VERSION 5.8 ;
BUSBITCHARS "[]" ;
DIVIDERCHAR "/" ;
UNITS
    DATABASE MICRONS 1000 ;
END UNITS

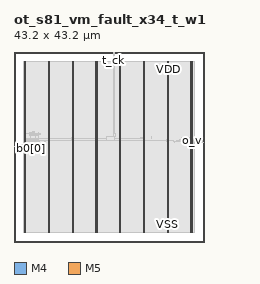
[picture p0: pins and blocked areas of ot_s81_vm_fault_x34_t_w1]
MACRO ot_s81_vm_fault_x34_t_w1
  FOREIGN ot_s81_vm_fault_x34_t_w1 0 0 ;
  CLASS BLOCK ;
  SIZE 43.2 BY 43.2 ;
  PIN b0[0]
    DIRECTION INPUT ;
    USE SIGNAL ;
    PORT
      LAYER M4 ;
        RECT  0 21.36 0.084 21.384 ;
    END
  END b0[0]
  PIN b0[1]
    DIRECTION INPUT ;
    USE SIGNAL ;
    PORT
      LAYER M4 ;
        RECT  0 21.456 0.084 21.48 ;
    END
  END b0[1]
  PIN b1[0]
    DIRECTION INPUT ;
    USE SIGNAL ;
    PORT
      LAYER M4 ;
        RECT  0 21.552 0.084 21.576 ;
    END
  END b1[0]
  PIN b1[1]
    DIRECTION INPUT ;
    USE SIGNAL ;
    PORT
      LAYER M4 ;
        RECT  0 21.648 0.084 21.672 ;
    END
  END b1[1]
  PIN b2[0]
    DIRECTION INPUT ;
    USE SIGNAL ;
    PORT
      LAYER M4 ;
        RECT  0 21.744 0.084 21.768 ;
    END
  END b2[0]
  PIN b2[1]
    DIRECTION INPUT ;
    USE SIGNAL ;
    PORT
      LAYER M4 ;
        RECT  0 21.84 0.084 21.864 ;
    END
  END b2[1]
  PIN bpar[0]
    DIRECTION INPUT ;
    USE SIGNAL ;
    PORT
      LAYER M4 ;
        RECT  0 21.936 0.084 21.96 ;
    END
  END bpar[0]
  PIN bpar[1]
    DIRECTION INPUT ;
    USE SIGNAL ;
    PORT
      LAYER M4 ;
        RECT  0 22.032 0.084 22.056 ;
    END
  END bpar[1]
  PIN bpar[2]
    DIRECTION INPUT ;
    USE SIGNAL ;
    PORT
      LAYER M4 ;
        RECT  0 22.128 0.084 22.152 ;
    END
  END bpar[2]
  PIN fault
    DIRECTION OUTPUT ;
    USE SIGNAL ;
    PORT
      LAYER M4 ;
        RECT  43.116 22.8 43.2 22.824 ;
    END
  END fault
  PIN o_d
    DIRECTION OUTPUT ;
    USE SIGNAL ;
    PORT
      LAYER M4 ;
        RECT  43.116 22.896 43.2 22.92 ;
    END
  END o_d
  PIN o_v
    DIRECTION OUTPUT ;
    USE SIGNAL ;
    PORT
      LAYER M4 ;
        RECT  43.116 22.992 43.2 23.016 ;
    END
  END o_v
  PIN s_mark
    DIRECTION INPUT ;
    USE SIGNAL ;
    PORT
      LAYER M4 ;
        RECT  0 22.224 0.084 22.248 ;
    END
  END s_mark
  PIN t_ck
    DIRECTION INPUT ;
    USE SIGNAL ;
    PORT
      LAYER M5 ;
        RECT  22.704 43.116 22.728 43.2 ;
    END
  END t_ck
  PIN t_rst_n
    DIRECTION INPUT ;
    USE SIGNAL ;
    PORT
      LAYER M5 ;
        RECT  22.8 43.116 22.824 43.2 ;
    END
  END t_rst_n
  PIN VDD
    DIRECTION INOUT ;
    USE POWER ;
    PORT
      LAYER M5 ;
        RECT  40.392 2.151 40.512 41.049 ;
        RECT  34.992 2.151 35.112 41.049 ;
        RECT  29.592 2.151 29.712 41.049 ;
        RECT  24.192 2.151 24.312 41.049 ;
        RECT  18.792 2.151 18.912 41.049 ;
        RECT  13.392 2.151 13.512 41.049 ;
        RECT  7.992 2.151 8.112 41.049 ;
        RECT  2.592 2.151 2.712 41.049 ;
    END
  END VDD
  PIN VSS
    DIRECTION INOUT ;
    USE GROUND ;
    PORT
      LAYER M5 ;
        RECT  40.2 2.137 40.32 41.063 ;
        RECT  34.8 2.137 34.92 41.063 ;
        RECT  29.4 2.137 29.52 41.063 ;
        RECT  24 2.137 24.12 41.063 ;
        RECT  18.6 2.137 18.72 41.063 ;
        RECT  13.2 2.137 13.32 41.063 ;
        RECT  7.8 2.137 7.92 41.063 ;
        RECT  2.4 2.137 2.52 41.063 ;
    END
  END VSS
  OBS
    LAYER RVTN ;
     RECT  2.16 2.16 41.04 2.295 ;
     RECT  2.16 2.565 41.04 2.835 ;
     RECT  2.16 3.105 41.04 3.375 ;
     RECT  2.16 3.645 41.04 3.915 ;
     RECT  2.16 4.185 41.04 4.455 ;
     RECT  2.16 4.725 41.04 4.995 ;
     RECT  2.16 5.265 41.04 5.535 ;
     RECT  2.16 5.805 41.04 6.075 ;
     RECT  2.16 6.345 41.04 6.615 ;
     RECT  2.16 6.885 41.04 7.155 ;
     RECT  2.16 7.425 41.04 7.695 ;
     RECT  2.16 7.965 41.04 8.235 ;
     RECT  2.16 8.505 41.04 8.775 ;
     RECT  2.16 9.045 41.04 9.315 ;
     RECT  2.16 9.585 41.04 9.855 ;
     RECT  2.16 10.125 41.04 10.395 ;
     RECT  2.16 10.665 41.04 10.935 ;
     RECT  2.16 11.205 41.04 11.475 ;
     RECT  2.16 11.745 41.04 12.015 ;
     RECT  2.16 12.285 41.04 12.555 ;
     RECT  2.16 12.825 41.04 13.095 ;
     RECT  2.16 13.365 41.04 13.635 ;
     RECT  2.16 13.905 41.04 14.175 ;
     RECT  2.16 14.445 41.04 14.715 ;
     RECT  2.16 14.985 41.04 15.255 ;
     RECT  2.16 15.525 41.04 15.795 ;
     RECT  2.16 16.065 41.04 16.335 ;
     RECT  2.16 16.605 41.04 16.875 ;
     RECT  2.16 17.145 41.04 17.415 ;
     RECT  2.16 17.685 41.04 17.955 ;
     RECT  2.16 18.225 41.04 18.495 ;
     RECT  2.16 18.765 41.04 19.035 ;
     RECT  2.16 19.305 41.04 19.575 ;
     RECT  2.16 19.845 41.04 20.115 ;
     RECT  2.16 20.385 41.04 20.655 ;
     RECT  2.16 20.925 41.04 21.195 ;
     RECT  2.16 21.465 41.04 21.735 ;
     RECT  2.16 22.005 41.04 22.275 ;
     RECT  2.16 22.545 41.04 22.815 ;
     RECT  2.16 23.085 41.04 23.355 ;
     RECT  2.16 23.625 41.04 23.895 ;
     RECT  2.16 24.165 41.04 24.435 ;
     RECT  2.16 24.705 41.04 24.975 ;
     RECT  2.16 25.245 41.04 25.515 ;
     RECT  2.16 25.785 41.04 26.055 ;
     RECT  2.16 26.325 41.04 26.595 ;
     RECT  2.16 26.865 41.04 27.135 ;
     RECT  2.16 27.405 41.04 27.675 ;
     RECT  2.16 27.945 41.04 28.215 ;
     RECT  2.16 28.485 41.04 28.755 ;
     RECT  2.16 29.025 41.04 29.295 ;
     RECT  2.16 29.565 41.04 29.835 ;
     RECT  2.16 30.105 41.04 30.375 ;
     RECT  2.16 30.645 41.04 30.915 ;
     RECT  2.16 31.185 41.04 31.455 ;
     RECT  2.16 31.725 41.04 31.995 ;
     RECT  2.16 32.265 41.04 32.535 ;
     RECT  2.16 32.805 41.04 33.075 ;
     RECT  2.16 33.345 41.04 33.615 ;
     RECT  2.16 33.885 41.04 34.155 ;
     RECT  2.16 34.425 41.04 34.695 ;
     RECT  2.16 34.965 41.04 35.235 ;
     RECT  2.16 35.505 41.04 35.775 ;
     RECT  2.16 36.045 41.04 36.315 ;
     RECT  2.16 36.585 41.04 36.855 ;
     RECT  2.16 37.125 41.04 37.395 ;
     RECT  2.16 37.665 41.04 37.935 ;
     RECT  2.16 38.205 41.04 38.475 ;
     RECT  2.16 38.745 41.04 39.015 ;
     RECT  2.16 39.285 41.04 39.555 ;
     RECT  2.16 39.825 41.04 40.095 ;
     RECT  2.16 40.365 41.04 40.635 ;
     RECT  2.16 40.905 41.04 41.04 ;
    LAYER RVTP ;
     RECT  2.16 2.295 41.04 2.565 ;
     RECT  2.16 2.835 41.04 3.105 ;
     RECT  2.16 3.375 41.04 3.645 ;
     RECT  2.16 3.915 41.04 4.185 ;
     RECT  2.16 4.455 41.04 4.725 ;
     RECT  2.16 4.995 41.04 5.265 ;
     RECT  2.16 5.535 41.04 5.805 ;
     RECT  2.16 6.075 41.04 6.345 ;
     RECT  2.16 6.615 41.04 6.885 ;
     RECT  2.16 7.155 41.04 7.425 ;
     RECT  2.16 7.695 41.04 7.965 ;
     RECT  2.16 8.235 41.04 8.505 ;
     RECT  2.16 8.775 41.04 9.045 ;
     RECT  2.16 9.315 41.04 9.585 ;
     RECT  2.16 9.855 41.04 10.125 ;
     RECT  2.16 10.395 41.04 10.665 ;
     RECT  2.16 10.935 41.04 11.205 ;
     RECT  2.16 11.475 41.04 11.745 ;
     RECT  2.16 12.015 41.04 12.285 ;
     RECT  2.16 12.555 41.04 12.825 ;
     RECT  2.16 13.095 41.04 13.365 ;
     RECT  2.16 13.635 41.04 13.905 ;
     RECT  2.16 14.175 41.04 14.445 ;
     RECT  2.16 14.715 41.04 14.985 ;
     RECT  2.16 15.255 41.04 15.525 ;
     RECT  2.16 15.795 41.04 16.065 ;
     RECT  2.16 16.335 41.04 16.605 ;
     RECT  2.16 16.875 41.04 17.145 ;
     RECT  2.16 17.415 41.04 17.685 ;
     RECT  2.16 17.955 41.04 18.225 ;
     RECT  2.16 18.495 41.04 18.765 ;
     RECT  2.16 19.035 41.04 19.305 ;
     RECT  2.16 19.575 41.04 19.845 ;
     RECT  2.16 20.115 41.04 20.385 ;
     RECT  2.16 20.655 41.04 20.925 ;
     RECT  2.16 21.195 41.04 21.465 ;
     RECT  2.16 21.735 41.04 22.005 ;
     RECT  2.16 22.275 41.04 22.545 ;
     RECT  2.16 22.815 41.04 23.085 ;
     RECT  2.16 23.355 41.04 23.625 ;
     RECT  2.16 23.895 41.04 24.165 ;
     RECT  2.16 24.435 41.04 24.705 ;
     RECT  2.16 24.975 41.04 25.245 ;
     RECT  2.16 25.515 41.04 25.785 ;
     RECT  2.16 26.055 41.04 26.325 ;
     RECT  2.16 26.595 41.04 26.865 ;
     RECT  2.16 27.135 41.04 27.405 ;
     RECT  2.16 27.675 41.04 27.945 ;
     RECT  2.16 28.215 41.04 28.485 ;
     RECT  2.16 28.755 41.04 29.025 ;
     RECT  2.16 29.295 41.04 29.565 ;
     RECT  2.16 29.835 41.04 30.105 ;
     RECT  2.16 30.375 41.04 30.645 ;
     RECT  2.16 30.915 41.04 31.185 ;
     RECT  2.16 31.455 41.04 31.725 ;
     RECT  2.16 31.995 41.04 32.265 ;
     RECT  2.16 32.535 41.04 32.805 ;
     RECT  2.16 33.075 41.04 33.345 ;
     RECT  2.16 33.615 41.04 33.885 ;
     RECT  2.16 34.155 41.04 34.425 ;
     RECT  2.16 34.695 41.04 34.965 ;
     RECT  2.16 35.235 41.04 35.505 ;
     RECT  2.16 35.775 41.04 36.045 ;
     RECT  2.16 36.315 41.04 36.585 ;
     RECT  2.16 36.855 41.04 37.125 ;
     RECT  2.16 37.395 41.04 37.665 ;
     RECT  2.16 37.935 41.04 38.205 ;
     RECT  2.16 38.475 41.04 38.745 ;
     RECT  2.16 39.015 41.04 39.285 ;
     RECT  2.16 39.555 41.04 39.825 ;
     RECT  2.16 40.095 41.04 40.365 ;
     RECT  2.16 40.635 41.04 40.905 ;
    LAYER M1 ;
     RECT  2.16 2.151 41.04 41.049 ;
    LAYER M2 ;
     RECT  0.535 21.438 2.16 21.456 ;
     RECT  0.535 22.212 2.16 22.23 ;
     RECT  2.16 2.151 41.04 41.049 ;
     RECT  41.04 23.796 42.179 23.814 ;
     RECT  41.04 22.626 43.115 22.644 ;
    LAYER M3 ;
     RECT  2.415 2.143 2.505 2.413 ;
     RECT  7.815 2.143 7.905 2.413 ;
     RECT  13.215 2.143 13.305 2.413 ;
     RECT  18.615 2.143 18.705 2.413 ;
     RECT  24.015 2.143 24.105 2.413 ;
     RECT  29.415 2.143 29.505 2.413 ;
     RECT  34.815 2.143 34.905 2.413 ;
     RECT  40.215 2.143 40.305 2.413 ;
     RECT  2.415 2.413 2.697 21.127 ;
     RECT  2.34 21.127 2.697 21.163 ;
     RECT  2.34 21.163 2.862 21.235 ;
     RECT  2.304 21.235 3.87 21.397 ;
     RECT  4.608 21.361 4.626 21.397 ;
     RECT  0.144 21.403 0.162 21.433 ;
     RECT  2.304 21.397 4.626 21.541 ;
     RECT  0.144 21.433 0.558 21.581 ;
     RECT  2.304 21.541 5.274 22.001 ;
     RECT  2.304 22.001 5.13 22.123 ;
     RECT  0.54 21.581 0.558 22.253 ;
     RECT  40.215 2.413 40.497 22.315 ;
     RECT  40.215 22.315 40.806 22.351 ;
     RECT  2.268 22.123 5.13 22.505 ;
     RECT  2.304 22.505 5.13 22.747 ;
     RECT  2.304 22.747 5.31 22.783 ;
     RECT  36.54 22.621 36.558 22.783 ;
     RECT  36.36 22.783 36.558 22.829 ;
     RECT  43.092 22.621 43.11 22.829 ;
     RECT  40.215 22.351 40.914 22.855 ;
     RECT  7.056 22.819 7.074 22.891 ;
     RECT  34.815 2.413 35.097 22.891 ;
     RECT  37.44 22.795 37.458 22.891 ;
     RECT  39.492 22.855 40.914 22.891 ;
     RECT  6.984 22.891 7.074 23.017 ;
     RECT  7.815 2.413 8.097 23.017 ;
     RECT  39.42 22.891 40.914 23.021 ;
     RECT  29.415 2.413 29.697 23.035 ;
     RECT  36.864 22.891 38.178 23.044 ;
     RECT  2.304 22.783 5.814 23.045 ;
     RECT  2.415 23.045 5.814 23.053 ;
     RECT  6.984 23.017 8.097 23.081 ;
     RECT  36.864 23.044 38.214 23.081 ;
     RECT  37.44 23.081 38.214 23.131 ;
     RECT  2.415 23.053 6.21 23.161 ;
     RECT  6.984 23.081 7.002 23.161 ;
     RECT  37.44 23.131 38.646 23.165 ;
     RECT  34.776 22.891 35.097 23.279 ;
     RECT  2.415 23.161 7.002 23.351 ;
     RECT  37.62 23.165 38.646 23.351 ;
     RECT  39.42 23.021 40.734 23.359 ;
     RECT  2.415 23.351 6.39 23.423 ;
     RECT  13.215 2.413 13.497 23.521 ;
     RECT  3.672 23.423 6.39 23.549 ;
     RECT  39.204 23.359 40.734 23.549 ;
     RECT  12.888 23.521 13.497 23.597 ;
     RECT  3.672 23.549 6.21 23.621 ;
     RECT  21.564 23.611 21.582 23.657 ;
     RECT  38.196 23.351 38.214 23.657 ;
     RECT  12.996 23.597 13.497 23.729 ;
     RECT  28.764 23.035 29.697 23.729 ;
     RECT  42.156 22.891 42.174 23.819 ;
     RECT  39.924 23.549 40.554 23.855 ;
     RECT  20.988 23.701 21.006 23.933 ;
     RECT  31.32 23.593 31.338 24.089 ;
     RECT  3.672 23.621 5.562 24.169 ;
     RECT  3.528 24.169 5.562 24.475 ;
     RECT  3.528 24.475 5.742 24.511 ;
     RECT  3.528 24.511 6.138 24.629 ;
     RECT  22.968 24.097 22.986 24.629 ;
     RECT  5.544 24.629 5.742 24.701 ;
     RECT  3.6 24.629 4.698 24.899 ;
     RECT  4.176 24.899 4.698 24.971 ;
     RECT  5.544 24.701 5.562 24.971 ;
     RECT  4.212 24.971 4.698 25.043 ;
     RECT  4.212 25.043 4.23 25.169 ;
     RECT  22.752 24.745 22.77 33.961 ;
     RECT  22.752 33.961 22.95 33.989 ;
     RECT  22.824 33.989 22.95 34.079 ;
     RECT  22.824 34.079 22.842 38.209 ;
     RECT  22.824 38.209 22.95 38.237 ;
     RECT  22.86 38.237 22.95 38.669 ;
     RECT  2.415 23.423 2.697 40.787 ;
     RECT  7.815 23.081 8.097 40.787 ;
     RECT  13.215 23.729 13.497 40.787 ;
     RECT  18.615 2.413 18.897 40.787 ;
     RECT  24.015 2.413 24.297 40.787 ;
     RECT  29.415 23.729 29.697 40.787 ;
     RECT  34.815 23.279 35.097 40.787 ;
     RECT  40.215 23.855 40.497 40.787 ;
     RECT  22.86 38.669 22.878 41.021 ;
     RECT  2.415 40.787 2.505 41.057 ;
     RECT  7.815 40.787 7.905 41.057 ;
     RECT  13.215 40.787 13.305 41.057 ;
     RECT  18.615 40.787 18.705 41.057 ;
     RECT  24.015 40.787 24.105 41.057 ;
     RECT  29.415 40.787 29.505 41.057 ;
     RECT  34.815 40.787 34.905 41.057 ;
     RECT  40.215 40.787 40.305 41.057 ;
    LAYER M4 ;
     RECT  0.06 21.36 0.569 22.248 ;
     RECT  0.569 21.36 2.408 22.152 ;
     RECT  2.408 2.148 2.512 41.052 ;
     RECT  2.512 2.418 2.704 40.782 ;
     RECT  2.704 21.408 4.133 21.432 ;
     RECT  2.704 22.992 4.405 23.016 ;
     RECT  4.405 22.176 4.451 23.352 ;
     RECT  4.451 22.176 4.492 22.2 ;
     RECT  4.451 23.328 4.885 23.352 ;
     RECT  2.704 24.576 4.931 24.6 ;
     RECT  4.885 23.328 5.641 23.592 ;
     RECT  5.641 23.04 7.808 23.592 ;
     RECT  7.808 2.148 7.912 41.052 ;
     RECT  7.912 2.418 8.104 40.782 ;
     RECT  8.104 23.04 12.985 23.592 ;
     RECT  12.985 23.04 13.208 23.64 ;
     RECT  13.208 2.148 13.312 41.052 ;
     RECT  13.312 2.418 13.504 40.782 ;
     RECT  13.504 23.04 18.608 23.64 ;
     RECT  18.608 2.148 18.712 41.052 ;
     RECT  18.712 2.418 18.904 40.782 ;
     RECT  18.904 23.04 20.977 23.64 ;
     RECT  20.977 23.04 22.739 23.928 ;
     RECT  22.789 40.992 22.889 41.016 ;
     RECT  22.739 23.04 24.008 23.64 ;
     RECT  24.008 2.148 24.112 41.052 ;
     RECT  24.112 2.418 24.304 40.782 ;
     RECT  24.304 23.04 29.408 23.64 ;
     RECT  29.408 2.148 29.512 41.052 ;
     RECT  29.512 2.418 29.704 40.782 ;
     RECT  29.704 23.04 34.808 23.064 ;
     RECT  34.808 2.148 34.912 41.052 ;
     RECT  34.912 2.418 35.104 40.782 ;
     RECT  35.104 23.04 36.285 23.064 ;
     RECT  36.285 22.8 36.371 23.064 ;
     RECT  36.371 22.8 37.429 22.824 ;
     RECT  37.429 22.8 37.469 23.16 ;
     RECT  37.469 23.136 38.657 23.16 ;
     RECT  40.208 2.148 40.312 41.052 ;
     RECT  40.312 2.418 40.504 40.782 ;
     RECT  40.504 22.992 42.145 23.016 ;
     RECT  42.145 22.896 43.081 23.016 ;
     RECT  43.081 22.8 43.164 23.016 ;
    LAYER M5 ;
     RECT  2.4 2.137 2.52 2.151 ;
     RECT  7.8 2.137 7.92 2.151 ;
     RECT  13.2 2.137 13.32 2.151 ;
     RECT  18.6 2.137 18.72 2.151 ;
     RECT  24 2.137 24.12 2.151 ;
     RECT  29.4 2.137 29.52 2.151 ;
     RECT  34.8 2.137 34.92 2.151 ;
     RECT  40.2 2.137 40.32 2.151 ;
     RECT  36.336 22.789 36.36 23.075 ;
     RECT  4.416 22.165 4.44 23.317 ;
     RECT  4.416 23.317 4.92 23.363 ;
     RECT  4.896 23.363 4.92 24.611 ;
     RECT  22.704 23.893 22.728 40.981 ;
     RECT  2.4 2.151 2.712 41.049 ;
     RECT  7.8 2.151 8.112 41.049 ;
     RECT  13.2 2.151 13.512 41.049 ;
     RECT  18.6 2.151 18.912 41.049 ;
     RECT  24 2.151 24.312 41.049 ;
     RECT  29.4 2.151 29.712 41.049 ;
     RECT  34.8 2.151 35.112 41.049 ;
     RECT  40.2 2.151 40.512 41.049 ;
     RECT  2.4 41.049 2.52 41.063 ;
     RECT  7.8 41.049 7.92 41.063 ;
     RECT  13.2 41.049 13.32 41.063 ;
     RECT  18.6 41.049 18.72 41.063 ;
     RECT  24 41.049 24.12 41.063 ;
     RECT  29.4 41.049 29.52 41.063 ;
     RECT  34.8 41.049 34.92 41.063 ;
     RECT  40.2 41.049 40.32 41.063 ;
     RECT  22.704 40.981 22.824 43.152 ;
  END
END ot_s81_vm_fault_x34_t_w1
END LIBRARY
